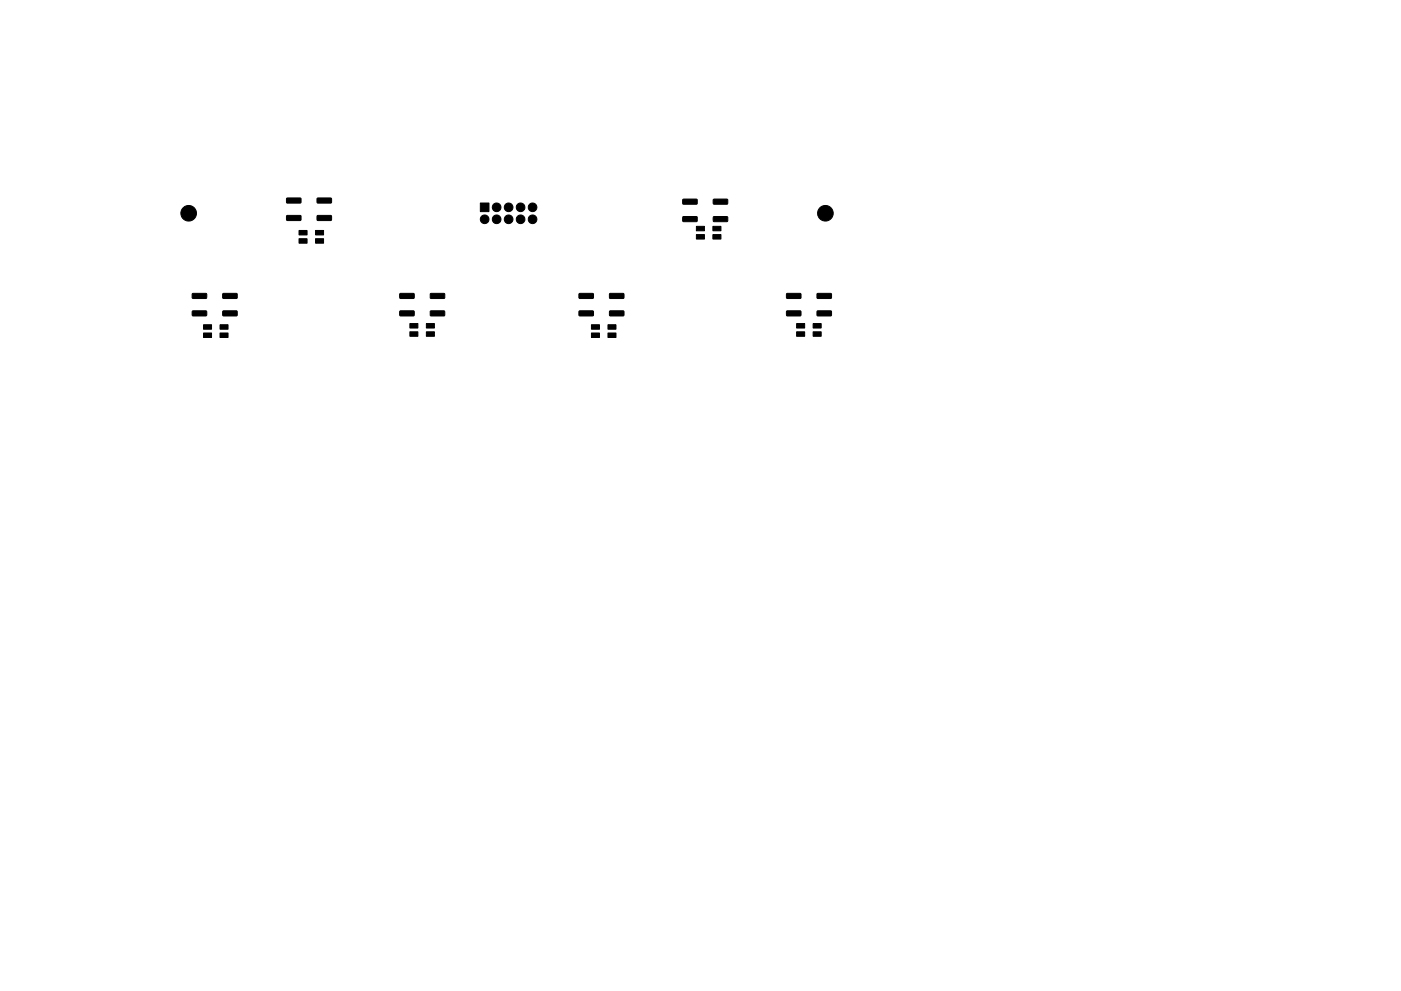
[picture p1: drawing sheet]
<svg xmlns="http://www.w3.org/2000/svg" width="297mm" height="210mm" viewBox="0 0 297 210" stroke-linecap="round" stroke-linejoin="round" font-family="sans-serif">
<g fill="#000" stroke="#000" stroke-width=".21">
<path d="M60.8 45.8l2.9-.1 .1 .2v.7l-.2 .2h-2.7l-.2-.2zM60.8 42.1l2.9-.1 .1 .2v.7l-.2 .2h-2.7l-.2-.2zM63.4 50.6h1.7v1h-1.7zM63.4 48.9h1.7v.9h-1.7zM66.9 50.6h1.7v1h-1.7zM66.9 48.9h1.7v.9h-1.7zM67.3 45.8l2.8-.1 .2 .2v.7l-.2 .2h-2.7l-.2-.2zM67.3 42.1l2.8-.1 .2 .2v.7l-.2 .2h-2.7l-.2-.2zM101.8 43.1h1.9v1.8h-1.9zM144.8 46l2.9-.1 .1 .2v.8l-.2 .1h-2.7l-.2-.1zM144.8 42.3l2.9-.1 .1 .2v.8l-.2 .1h-2.7l-.2-.1zM147.6 49.8h1.8v.9h-1.8z"/>
<path d="M147.6 48h1.8v1h-1.8zM151.1 49.8h1.8v.9h-1.8zM151.1 48h1.8v1h-1.8zM151.3 46l2.8-.1 .2 .2v.8l-.2 .1h-2.7l-.2-.1zM151.3 42.3l2.8-.1 .2 .2v.8l-.2 .1h-2.7l-.2-.1zM40.8 66l2.9-.1 .1 .2v.8l-.2 .1h-2.7l-.2-.1zM40.8 62.3l2.9-.1 .1 .2v.8l-.2 .1h-2.7l-.2-.1zM43.1 70.6h1.8v1h-1.8zM43.1 68.9h1.8v.9h-1.8zM46.6 70.6h1.8v1h-1.8zM46.6 68.9h1.8v.9h-1.8zM47.3 66l2.8-.1 .2 .2v.8l-.2 .1h-2.7l-.2-.1z"/>
<path d="M47.3 62.3l2.8-.1 .2 .2v.8l-.2 .1h-2.7l-.2-.1zM84.8 66l2.9-.1 .1 .2v.8l-.2 .1h-2.7l-.2-.1zM84.8 62.3l2.9-.1 .1 .2v.8l-.2 .1h-2.7l-.2-.1zM86.9 70.4h1.7v.9h-1.7zM86.9 68.6h1.7v1h-1.7zM90.4 70.4h1.7v.9h-1.7zM90.4 68.6h1.7v1h-1.7zM91.3 66l2.8-.1 .2 .2v.8l-.2 .1h-2.7l-.2-.1zM91.3 62.3l2.8-.1 .2 .2v.8l-.2 .1h-2.7l-.2-.1zM122.8 66l2.9-.1 .1 .2v.8l-.2 .1h-2.7l-.2-.1zM122.8 62.3l2.9-.1 .1 .2v.8l-.2 .1h-2.7l-.2-.1zM125.4 70.6h1.7v1h-1.7z"/>
<path d="M125.4 68.9h1.7v.9h-1.7zM128.9 70.6h1.7v1h-1.7zM128.9 68.9h1.7v.9h-1.7zM129.3 66l2.8-.1 .2 .2v.8l-.2 .1h-2.7l-.2-.1zM129.3 62.3l2.8-.1 .2 .2v.8l-.2 .1h-2.7l-.2-.1zM166.8 66l2.9-.1 .1 .2v.8l-.2 .1h-2.7l-.2-.1zM166.8 62.3l2.9-.1 .1 .2v.8l-.2 .1h-2.7l-.2-.1zM168.9 70.4h1.7v.9h-1.7zM168.9 68.6h1.7v1h-1.7zM172.4 70.4h1.7v.9h-1.7zM172.4 68.6h1.7v1h-1.7zM173.3 66l2.8-.1 .2 .2v.8l-.2 .1h-2.7l-.2-.1z"/>
<path d="M173.3 62.3l2.8-.1 .2 .2v.8l-.2 .1h-2.7l-.2-.1z"/>
<circle cx="40" cy="45.2" r="1.65"/>
<circle cx="102.8" cy="46.5" r=".92"/>
<circle cx="105.3" cy="44" r=".92"/>
<circle cx="105.3" cy="46.5" r=".92"/>
<circle cx="107.8" cy="44" r=".92"/>
<circle cx="107.8" cy="46.5" r=".92"/>
<circle cx="110.4" cy="44" r=".92"/>
<circle cx="110.4" cy="46.5" r=".92"/>
<circle cx="112.9" cy="44" r=".92"/>
<circle cx="112.9" cy="46.5" r=".92"/>
<circle cx="175" cy="45.2" r="1.65"/>
</g>
</svg>
